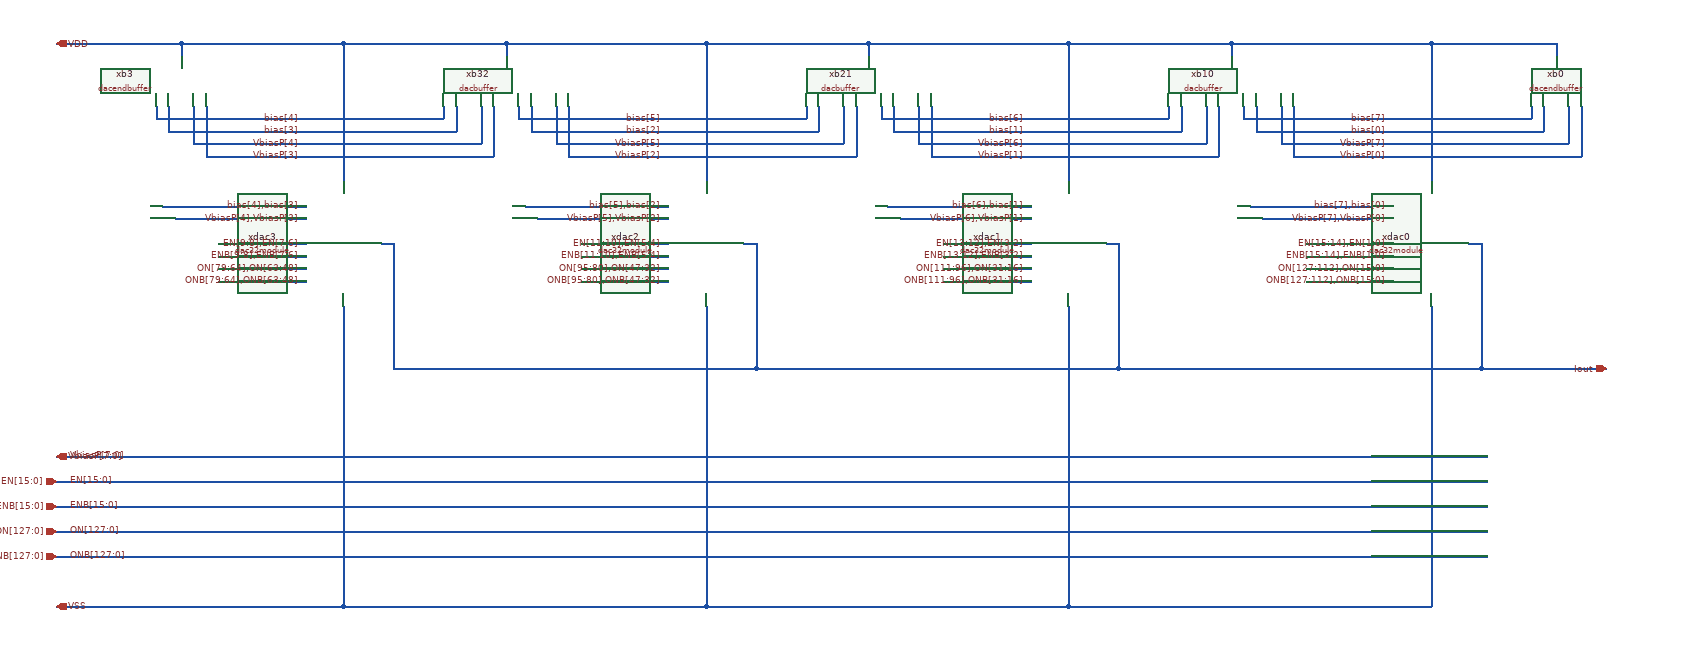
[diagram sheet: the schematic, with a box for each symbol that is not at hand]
v {xschem version=3.4.7 file_version=1.2}
G {}
K {}
V {}
S {}
E {}
N 600 -960 600 -740 {lab=VDD}
N 1180 -960 1180 -740 {lab=VDD}
N 2340 -960 2340 -740 {lab=VDD}
N 1760 -960 1760 -740 {lab=VDD}
N 1760 -540 1760 -60 {lab=VSS}
N 600 -540 600 -60 {lab=VSS}
N 2400 -640 2420 -640 {lab=Iout}
N 2420 -640 2420 -440 {lab=Iout}
N 680 -640 680 -440 {lab=Iout}
N 660 -640 680 -640 {lab=Iout}
N 1240 -640 1260 -640 {lab=Iout}
N 1260 -640 1260 -440 {lab=Iout}
N 1820 -640 1840 -640 {lab=Iout}
N 1840 -640 1840 -440 {lab=Iout}
N 340 -960 600 -960 {lab=VDD}
N 140 -60 600 -60 {lab=VSS}
N 330 -680 540 -680 {lab=VbiasP[4],VbiasP[3]}
N 310 -700 540 -700 {lab=bias[4],bias[3]}
N 760 -860 760 -840 {lab=bias[4]}
N 300 -840 760 -840 {lab=bias[4]}
N 300 -860 300 -840 {lab=bias[4]}
N 320 -820 780 -820 {lab=bias[3]}
N 320 -860 320 -820 {lab=bias[3]}
N 780 -860 780 -820 {lab=bias[3]}
N 820 -860 820 -800 {lab=VbiasP[4]}
N 360 -800 820 -800 {lab=VbiasP[4]}
N 360 -860 360 -800 {lab=VbiasP[4]}
N 840 -860 840 -780 {lab=VbiasP[3]}
N 380 -780 840 -780 {lab=VbiasP[3]}
N 380 -860 380 -780 {lab=VbiasP[3]}
N 910 -680 1120 -680 {lab=VbiasP[5],VbiasP[2]}
N 890 -700 1120 -700 {lab=bias[5],bias[2]}
N 1180 -60 1760 -60 {lab=VSS}
N 680 -440 1260 -440 {lab=Iout}
N 1340 -860 1340 -840 {lab=bias[5]}
N 880 -840 1340 -840 {lab=bias[5]}
N 880 -860 880 -840 {lab=bias[5]}
N 900 -820 1360 -820 {lab=bias[2]}
N 900 -860 900 -820 {lab=bias[2]}
N 1360 -860 1360 -820 {lab=bias[2]}
N 1400 -860 1400 -800 {lab=VbiasP[5]}
N 940 -800 1400 -800 {lab=VbiasP[5]}
N 940 -860 940 -800 {lab=VbiasP[5]}
N 1420 -860 1420 -780 {lab=VbiasP[2]}
N 960 -780 1420 -780 {lab=VbiasP[2]}
N 960 -860 960 -780 {lab=VbiasP[2]}
N 1920 -860 1920 -840 {lab=bias[6]}
N 1460 -840 1920 -840 {lab=bias[6]}
N 1460 -860 1460 -840 {lab=bias[6]}
N 1480 -820 1940 -820 {lab=bias[1]}
N 1480 -860 1480 -820 {lab=bias[1]}
N 1940 -860 1940 -820 {lab=bias[1]}
N 1980 -860 1980 -800 {lab=VbiasP[6]}
N 1520 -800 1980 -800 {lab=VbiasP[6]}
N 1520 -860 1520 -800 {lab=VbiasP[6]}
N 2000 -860 2000 -780 {lab=VbiasP[1]}
N 1540 -780 2000 -780 {lab=VbiasP[1]}
N 1540 -860 1540 -780 {lab=VbiasP[1]}
N 2500 -860 2500 -840 {lab=bias[7]}
N 2040 -840 2500 -840 {lab=bias[7]}
N 2040 -860 2040 -840 {lab=bias[7]}
N 2060 -820 2520 -820 {lab=bias[0]}
N 2060 -860 2060 -820 {lab=bias[0]}
N 2520 -860 2520 -820 {lab=bias[0]}
N 2560 -860 2560 -800 {lab=VbiasP[7]}
N 2100 -860 2100 -800 {lab=VbiasP[7]}
N 2580 -860 2580 -780 {lab=VbiasP[0]}
N 2120 -860 2120 -780 {lab=VbiasP[0]}
N 1490 -680 1700 -680 {lab=VbiasP[6],VbiasP[1]}
N 1470 -700 1700 -700 {lab=bias[6],bias[1]}
N 2070 -680 2280 -680 {lab=VbiasP[7],VbiasP[0]}
N 2050 -700 2280 -700 {lab=bias[7],bias[0]}
N 1440 -960 1760 -960 {lab=VDD}
N 1260 -440 1840 -440 {lab=Iout}
N 2020 -960 2340 -960 {lab=VDD}
N 2540 -960 2540 -940 {lab=VDD}
N 2020 -960 2020 -940 {lab=VDD}
N 1760 -960 2020 -960 {lab=VDD}
N 1440 -960 1440 -940 {lab=VDD}
N 1180 -960 1440 -960 {lab=VDD}
N 860 -960 860 -940 {lab=VDD}
N 600 -960 860 -960 {lab=VDD}
N 860 -960 1180 -960 {lab=VDD}
N 1760 -60 2340 -60 {lab=VSS}
N 400 -640 540 -640 {lab=EN[9:8],EN[7:6]}
N 400 -620 540 -620 {lab=ENB[9:8],ENB[7:6]}
N 400 -600 540 -600 {lab=ON[79:64],ON[63:48]}
N 400 -580 540 -580 {lab=ONB[79:64],ONB[63:48]}
N 980 -640 1120 -640 {lab=EN[11:10],EN[5:4]}
N 980 -620 1120 -620 {lab=ENB[11:10],ENB[5:4]}
N 980 -600 1120 -600 {lab=ON[95:80],ON[47:32]}
N 980 -580 1120 -580 {lab=ONB[95:80],ONB[47:32]}
N 2140 -640 2280 -640 {lab=EN[15:14],EN[1:0]}
N 2140 -620 2280 -620 {lab=ENB[15:14],ENB[1:0]}
N 2140 -600 2280 -600 {lab=ON[127:112],ON[15:0]}
N 2140 -580 2280 -580 {lab=ONB[127:112],ONB[15:0]}
N 340 -960 340 -940 {lab=VDD}
N 140 -960 340 -960 {lab=VDD}
N 1840 -440 2420 -440 {lab=Iout}
N 1560 -640 1700 -640 {lab=EN[13:12],EN[3:2]}
N 1560 -620 1700 -620 {lab=ENB[13:12],ENB[3:2]}
N 1560 -600 1700 -600 {lab=ON[111:96],ON[31:16]}
N 1560 -580 1700 -580 {lab=ONB[111:96],ONB[31:16]}
N 2340 -960 2540 -960 {lab=VDD}
N 2100 -800 2560 -800 {lab=VbiasP[7]}
N 2120 -780 2580 -780 {lab=VbiasP[0]}
N 140 -300 2430 -300 {lab=VbiasP[7:0]}
N 140 -260 2430 -260 {lab=EN[15:0]}
N 140 -220 2430 -220 {lab=ENB[15:0]}
N 2420 -440 2620 -440 {lab=Iout}
N 140 -180 2430 -180 {lab=ON[127:0]}
N 140 -140 2430 -140 {lab=ONB[127:0]}
N 1180 -540 1180 -60 {lab=VSS}
N 600 -60 1180 -60 {lab=VSS}
N 2340 -540 2340 -60 {lab=VSS}
C {title.sym} 160 0 0 0 {name=l1 author="Christoph Maier"}
C {iopin.sym} 2620 -440 0 0 {name=p4 lab=Iout}
C {dac32module.sym} 600 -640 0 0 {name=xdac3}
C {dac32module.sym} 1180 -640 0 0 {name=xdac2}
C {ipin.sym} 140 -180 0 0 {name=p7 sig_type=std_logic lab=ON[127:0]}
C {ipin.sym} 140 -140 0 0 {name=p8 sig_type=std_logic lab=ONB[127:0]}
C {iopin.sym} 140 -60 0 1 {name=p2 lab=VSS}
C {iopin.sym} 140 -960 0 1 {name=p1 lab=VDD}
C {iopin.sym} 140 -300 0 1 {name=p5 lab=VbiasP[7:0]}
C {dac32module.sym} 2340 -640 0 0 {name=xdac0}
C {dac32module.sym} 1760 -640 0 0 {name=xdac1}
C {ipin.sym} 140 -260 0 0 {name=p14 sig_type=std_logic lab=EN[15:0]}
C {ipin.sym} 140 -220 0 0 {name=p15 sig_type=std_logic lab=ENB[15:0]}
C {lab_wire.sym} 160 -300 0 1 {name=p16 lab=VbiasP[7:0]}
C {lab_wire.sym} 160 -260 0 1 {name=p26 lab=EN[15:0]}
C {lab_wire.sym} 160 -220 0 1 {name=p27 lab=ENB[15:0]}
C {lab_wire.sym} 160 -180 0 1 {name=p28 lab=ON[127:0]}
C {lab_wire.sym} 160 -140 0 1 {name=p29 lab=ONB[127:0]}
C {dacbuffer.sym} 860 -900 0 0 {name=xb32}
C {dacbuffer.sym} 1440 -900 0 0 {name=xb21}
C {dacbuffer.sym} 2020 -900 0 0 {name=xb10}
C {dacendbuffer.sym} 340 -900 0 0 {name=xb3}
C {dacendbuffer.sym} 2540 -900 0 0 {name=xb0}
C {lab_wire.sym} 530 -600 0 0 {name=p3 lab=ON[79:64],ON[63:48]}
C {lab_wire.sym} 530 -580 0 0 {name=p6 lab=ONB[79:64],ONB[63:48]}
C {lab_wire.sym} 530 -640 0 0 {name=p9 lab=EN[9:8],EN[7:6]}
C {lab_wire.sym} 530 -620 0 0 {name=p10 lab=ENB[9:8],ENB[7:6]}
C {lab_wire.sym} 1110 -600 0 0 {name=p11 lab=ON[95:80],ON[47:32]}
C {lab_wire.sym} 1110 -580 0 0 {name=p12 lab=ONB[95:80],ONB[47:32]}
C {lab_wire.sym} 1110 -640 0 0 {name=p13 lab=EN[11:10],EN[5:4]}
C {lab_wire.sym} 1110 -620 0 0 {name=p17 lab=ENB[11:10],ENB[5:4]}
C {lab_wire.sym} 1690 -600 0 0 {name=p18 lab=ON[111:96],ON[31:16]}
C {lab_wire.sym} 1690 -580 0 0 {name=p19 lab=ONB[111:96],ONB[31:16]}
C {lab_wire.sym} 1690 -640 0 0 {name=p20 lab=EN[13:12],EN[3:2]}
C {lab_wire.sym} 1690 -620 0 0 {name=p21 lab=ENB[13:12],ENB[3:2]}
C {lab_wire.sym} 2270 -600 0 0 {name=p22 lab=ON[127:112],ON[15:0]}
C {lab_wire.sym} 2270 -580 0 0 {name=p23 lab=ONB[127:112],ONB[15:0]}
C {lab_wire.sym} 2270 -640 0 0 {name=p24 lab=EN[15:14],EN[1:0]}
C {lab_wire.sym} 2270 -620 0 0 {name=p25 lab=ENB[15:14],ENB[1:0]}
C {lab_wire.sym} 530 -680 0 0 {name=p30 lab=VbiasP[4],VbiasP[3]}
C {lab_wire.sym} 530 -700 0 0 {name=p31 lab=bias[4],bias[3]}
C {lab_wire.sym} 530 -840 0 0 {name=p32 lab=bias[4]}
C {lab_wire.sym} 530 -820 0 0 {name=p33 lab=bias[3]}
C {lab_wire.sym} 530 -800 0 0 {name=p34 lab=VbiasP[4]}
C {lab_wire.sym} 530 -780 0 0 {name=p35 lab=VbiasP[3]}
C {lab_wire.sym} 1110 -680 0 0 {name=p36 lab=VbiasP[5],VbiasP[2]}
C {lab_wire.sym} 1110 -700 0 0 {name=p37 lab=bias[5],bias[2]}
C {lab_wire.sym} 1110 -820 0 0 {name=p38 lab=bias[2]}
C {lab_wire.sym} 1110 -800 0 0 {name=p39 lab=VbiasP[5]}
C {lab_wire.sym} 1110 -780 0 0 {name=p40 lab=VbiasP[2]}
C {lab_wire.sym} 1110 -840 0 0 {name=p41 lab=bias[5]}
C {lab_wire.sym} 1690 -680 0 0 {name=p42 lab=VbiasP[6],VbiasP[1]}
C {lab_wire.sym} 1690 -700 0 0 {name=p43 lab=bias[6],bias[1]}
C {lab_wire.sym} 1690 -820 0 0 {name=p44 lab=bias[1]}
C {lab_wire.sym} 1690 -800 0 0 {name=p45 lab=VbiasP[6]}
C {lab_wire.sym} 1690 -780 0 0 {name=p46 lab=VbiasP[1]}
C {lab_wire.sym} 1690 -840 0 0 {name=p47 lab=bias[6]}
C {lab_wire.sym} 2270 -680 0 0 {name=p48 lab=VbiasP[7],VbiasP[0]}
C {lab_wire.sym} 2270 -700 0 0 {name=p49 lab=bias[7],bias[0]}
C {lab_wire.sym} 2270 -820 0 0 {name=p50 lab=bias[0]}
C {lab_wire.sym} 2270 -800 0 0 {name=p51 lab=VbiasP[7]}
C {lab_wire.sym} 2270 -780 0 0 {name=p52 lab=VbiasP[0]}
C {lab_wire.sym} 2270 -840 0 0 {name=p53 lab=bias[7]}
